One B-rep face of a CAD part: STEP entity #32192.
In plain terms, the planar face has unit normal (0, 1, 0).
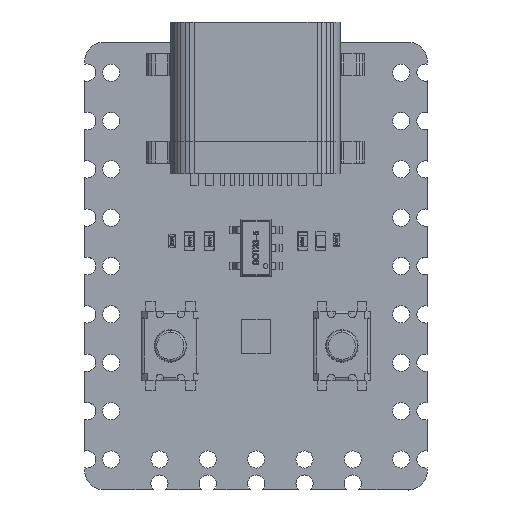
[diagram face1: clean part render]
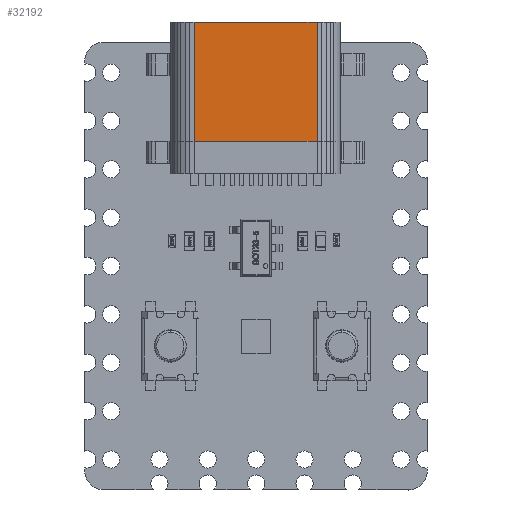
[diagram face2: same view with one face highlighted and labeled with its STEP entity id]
Its self-contained STEP definition (entity closure, numbers rounded to 3 decimals):
#29823 = PLANE('',#29824);
#29824 = AXIS2_PLACEMENT_3D('',#29825,#29826,#29827);
#29825 = CARTESIAN_POINT('',(-0.006,0.012,
    6.26));
#29826 = DIRECTION('',(0.,0.,1.));
#29827 = DIRECTION('',(1.,0.,0.));
#29879 = PLANE('',#29880);
#29880 = AXIS2_PLACEMENT_3D('',#29881,#29882,#29883);
#29881 = CARTESIAN_POINT('',(-0.006,0.012,
    0.));
#29882 = DIRECTION('',(0.,0.,1.));
#29883 = DIRECTION('',(1.,0.,0.));
#31009 = VERTEX_POINT('',#31010);
#31010 = CARTESIAN_POINT('',(3.221,1.592,6.26));
#31024 = PLANE('',#31025);
#31025 = AXIS2_PLACEMENT_3D('',#31026,#31027,#31028);
#31026 = CARTESIAN_POINT('',(3.475,1.569,0.));
#31027 = DIRECTION('',(-0.094,-0.996,0.));
#31028 = DIRECTION('',(0.996,-0.094,0.));
#31036 = EDGE_CURVE('',#31009,#31037,#31039,.T.);
#31037 = VERTEX_POINT('',#31038);
#31038 = CARTESIAN_POINT('',(-3.233,1.592,6.26));
#31039 = SURFACE_CURVE('',#31040,(#31044,#31051),.PCURVE_S1.);
#31040 = LINE('',#31041,#31042);
#31041 = CARTESIAN_POINT('',(-0.006,1.592,6.26));
#31042 = VECTOR('',#31043,1.);
#31043 = DIRECTION('',(-1.,0.,0.));
#31044 = PCURVE('',#29823,#31045);
#31045 = DEFINITIONAL_REPRESENTATION('',(#31046),#31050);
#31046 = LINE('',#31047,#31048);
#31047 = CARTESIAN_POINT('',(0.,1.581));
#31048 = VECTOR('',#31049,1.);
#31049 = DIRECTION('',(-1.,0.));
#31050 = ( GEOMETRIC_REPRESENTATION_CONTEXT(2) 
PARAMETRIC_REPRESENTATION_CONTEXT() REPRESENTATION_CONTEXT('2D SPACE',''
  ) );
#31051 = PCURVE('',#31052,#31057);
#31052 = PLANE('',#31053);
#31053 = AXIS2_PLACEMENT_3D('',#31054,#31055,#31056);
#31054 = CARTESIAN_POINT('',(-3.233,1.592,0.));
#31055 = DIRECTION('',(0.,1.,0.));
#31056 = DIRECTION('',(0.,0.,1.));
#31057 = DEFINITIONAL_REPRESENTATION('',(#31058),#31062);
#31058 = LINE('',#31059,#31060);
#31059 = CARTESIAN_POINT('',(6.26,3.227));
#31060 = VECTOR('',#31061,1.);
#31061 = DIRECTION('',(0.,-1.));
#31062 = ( GEOMETRIC_REPRESENTATION_CONTEXT(2) 
PARAMETRIC_REPRESENTATION_CONTEXT() REPRESENTATION_CONTEXT('2D SPACE',''
  ) );
#31080 = PLANE('',#31081);
#31081 = AXIS2_PLACEMENT_3D('',#31082,#31083,#31084);
#31082 = CARTESIAN_POINT('',(-3.233,1.592,0.));
#31083 = DIRECTION('',(0.094,-0.996,0.));
#31084 = DIRECTION('',(0.996,0.094,0.));
#32192 = ADVANCED_FACE('',(#32193),#31052,.T.);
#32193 = FACE_BOUND('',#32194,.T.);
#32194 = EDGE_LOOP('',(#32195,#32196,#32219,#32242));
#32195 = ORIENTED_EDGE('',*,*,#31036,.F.);
#32196 = ORIENTED_EDGE('',*,*,#32197,.T.);
#32197 = EDGE_CURVE('',#31009,#32198,#32200,.T.);
#32198 = VERTEX_POINT('',#32199);
#32199 = CARTESIAN_POINT('',(3.221,1.592,0.));
#32200 = SURFACE_CURVE('',#32201,(#32205,#32212),.PCURVE_S1.);
#32201 = LINE('',#32202,#32203);
#32202 = CARTESIAN_POINT('',(3.221,1.592,0.));
#32203 = VECTOR('',#32204,1.);
#32204 = DIRECTION('',(0.,0.,-1.));
#32205 = PCURVE('',#31052,#32206);
#32206 = DEFINITIONAL_REPRESENTATION('',(#32207),#32211);
#32207 = LINE('',#32208,#32209);
#32208 = CARTESIAN_POINT('',(0.,6.454));
#32209 = VECTOR('',#32210,1.);
#32210 = DIRECTION('',(-1.,0.));
#32211 = ( GEOMETRIC_REPRESENTATION_CONTEXT(2) 
PARAMETRIC_REPRESENTATION_CONTEXT() REPRESENTATION_CONTEXT('2D SPACE',''
  ) );
#32212 = PCURVE('',#31024,#32213);
#32213 = DEFINITIONAL_REPRESENTATION('',(#32214),#32218);
#32214 = LINE('',#32215,#32216);
#32215 = CARTESIAN_POINT('',(-0.254,0.));
#32216 = VECTOR('',#32217,1.);
#32217 = DIRECTION('',(0.,-1.));
#32218 = ( GEOMETRIC_REPRESENTATION_CONTEXT(2) 
PARAMETRIC_REPRESENTATION_CONTEXT() REPRESENTATION_CONTEXT('2D SPACE',''
  ) );
#32219 = ORIENTED_EDGE('',*,*,#32220,.T.);
#32220 = EDGE_CURVE('',#32198,#32221,#32223,.T.);
#32221 = VERTEX_POINT('',#32222);
#32222 = CARTESIAN_POINT('',(-3.233,1.592,0.));
#32223 = SURFACE_CURVE('',#32224,(#32228,#32235),.PCURVE_S1.);
#32224 = LINE('',#32225,#32226);
#32225 = CARTESIAN_POINT('',(-0.006,1.592,0.
    ));
#32226 = VECTOR('',#32227,1.);
#32227 = DIRECTION('',(-1.,0.,0.));
#32228 = PCURVE('',#31052,#32229);
#32229 = DEFINITIONAL_REPRESENTATION('',(#32230),#32234);
#32230 = LINE('',#32231,#32232);
#32231 = CARTESIAN_POINT('',(0.,3.227));
#32232 = VECTOR('',#32233,1.);
#32233 = DIRECTION('',(0.,-1.));
#32234 = ( GEOMETRIC_REPRESENTATION_CONTEXT(2) 
PARAMETRIC_REPRESENTATION_CONTEXT() REPRESENTATION_CONTEXT('2D SPACE',''
  ) );
#32235 = PCURVE('',#29879,#32236);
#32236 = DEFINITIONAL_REPRESENTATION('',(#32237),#32241);
#32237 = LINE('',#32238,#32239);
#32238 = CARTESIAN_POINT('',(0.,1.581));
#32239 = VECTOR('',#32240,1.);
#32240 = DIRECTION('',(-1.,0.));
#32241 = ( GEOMETRIC_REPRESENTATION_CONTEXT(2) 
PARAMETRIC_REPRESENTATION_CONTEXT() REPRESENTATION_CONTEXT('2D SPACE',''
  ) );
#32242 = ORIENTED_EDGE('',*,*,#32243,.T.);
#32243 = EDGE_CURVE('',#32221,#31037,#32244,.T.);
#32244 = SURFACE_CURVE('',#32245,(#32249,#32256),.PCURVE_S1.);
#32245 = LINE('',#32246,#32247);
#32246 = CARTESIAN_POINT('',(-3.233,1.592,0.));
#32247 = VECTOR('',#32248,1.);
#32248 = DIRECTION('',(0.,0.,1.));
#32249 = PCURVE('',#31052,#32250);
#32250 = DEFINITIONAL_REPRESENTATION('',(#32251),#32255);
#32251 = LINE('',#32252,#32253);
#32252 = CARTESIAN_POINT('',(0.,0.));
#32253 = VECTOR('',#32254,1.);
#32254 = DIRECTION('',(1.,0.));
#32255 = ( GEOMETRIC_REPRESENTATION_CONTEXT(2) 
PARAMETRIC_REPRESENTATION_CONTEXT() REPRESENTATION_CONTEXT('2D SPACE',''
  ) );
#32256 = PCURVE('',#31080,#32257);
#32257 = DEFINITIONAL_REPRESENTATION('',(#32258),#32262);
#32258 = LINE('',#32259,#32260);
#32259 = CARTESIAN_POINT('',(0.,0.));
#32260 = VECTOR('',#32261,1.);
#32261 = DIRECTION('',(0.,1.));
#32262 = ( GEOMETRIC_REPRESENTATION_CONTEXT(2) 
PARAMETRIC_REPRESENTATION_CONTEXT() REPRESENTATION_CONTEXT('2D SPACE',''
  ) );
